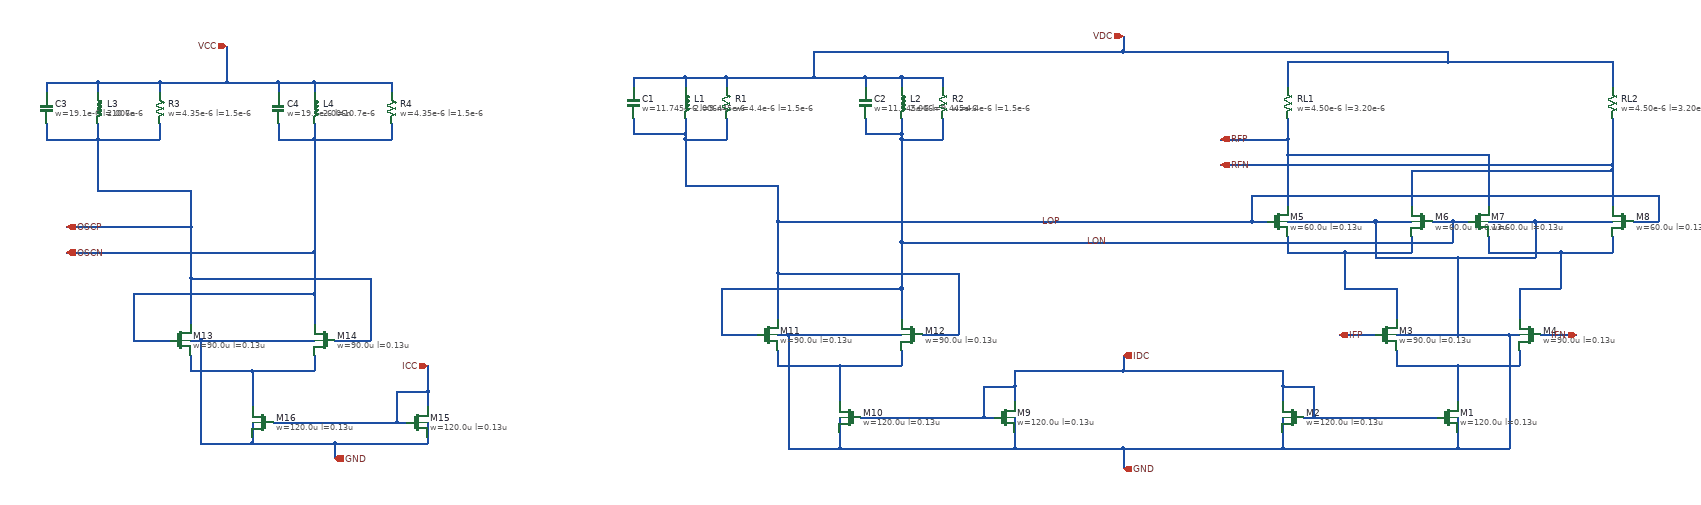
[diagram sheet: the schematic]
v {xschem version=3.4.5 file_version=1.2
}
G {}
K {}
V {}
S {}
E {}
N 530 -10 530 20 {
lab=#net1}
N 650 20 770 20 {
lab=#net1}
N 770 -10 770 20 {
lab=#net1}
N 650 20 650 90 {
lab=#net1}
N 530 20 650 20 {
lab=#net1}
N 370 120 610 120 {
lab=IDC}
N 310 120 310 180 {
lab=GND}
N 650 120 650 180 {
lab=GND}
N 310 60 310 90 {
lab=IDC}
N 310 60 370 60 {
lab=IDC}
N 310 30 310 60 {
lab=IDC}
N 370 60 370 120 {
lab=IDC}
N 350 120 370 120 {
lab=IDC}
N 420 -40 490 -40 {
lab=IFP}
N 810 -40 880 -40 {
lab=IFN}
N 320 -230 320 -200 {
lab=#net2}
N 430 -200 560 -200 {
lab=#net2}
N 560 -230 560 -200 {
lab=#net2}
N 710 -230 710 -200 {
lab=#net3}
N 850 -200 950 -200 {
lab=#net3}
N 950 -230 950 -200 {
lab=#net3}
N 530 -130 530 -70 {
lab=#net2}
N 430 -130 530 -130 {
lab=#net2}
N 430 -200 430 -130 {
lab=#net2}
N 320 -200 430 -200 {
lab=#net2}
N 770 -130 770 -70 {
lab=#net3}
N 770 -130 850 -130 {
lab=#net3}
N 850 -200 850 -130 {
lab=#net3}
N 710 -200 850 -200 {
lab=#net3}
N 640 -260 670 -260 {
lab=LON}
N 990 -260 1040 -260 {
lab=LOP}
N 1040 -310 1040 -260 {
lab=LOP}
N 250 -310 1040 -310 {
lab=LOP}
N 250 -310 250 -260 {
lab=LOP}
N 250 -260 280 -260 {
lab=LOP}
N 640 -260 640 -220 {
lab=LON}
N 600 -260 640 -260 {
lab=LON}
N 320 -390 320 -290 {
lab=RFP}
N 950 -360 950 -290 {
lab=RFN}
N 560 -360 950 -360 {
lab=RFN}
N 950 -370 950 -360 {
lab=RFN}
N 710 -390 710 -290 {
lab=RFP}
N 320 -390 710 -390 {
lab=RFP}
N 320 -420 320 -390 {
lab=RFP}
N 320 -570 320 -520 {
lab=VDC}
N 630 -570 950 -570 {
lab=VDC}
N 950 -570 950 -520 {
lab=VDC}
N 630 -590 630 -570 {
lab=VDC}
N 320 -570 630 -570 {
lab=VDC}
N 0 180 0 220 {
lab=GND}
N 310 180 650 180 {
lab=GND}
N 750 -40 770 -40 {
lab=GND}
N 490 -260 560 -260 {
lab=GND}
N 800 -260 950 -260 {
lab=GND}
N 750 -40 750 180 {
lab=GND}
N 650 -40 750 -40 {
lab=GND}
N 650 180 750 180 {
lab=GND}
N 490 -260 490 -190 {
lab=GND}
N 320 -260 490 -260 {
lab=GND}
N 650 -190 800 -190 {
lab=GND}
N 800 -260 800 -190 {
lab=GND}
N 710 -260 800 -260 {
lab=GND}
N 650 -190 650 -40 {
lab=GND}
N 490 -190 650 -190 {
lab=GND}
N 530 -40 650 -40 {
lab=GND}
N -430 -10 -430 20 {
lab=#net4}
N -670 20 -550 20 {
lab=#net4}
N -670 -10 -670 20 {
lab=#net4}
N -550 20 -550 90 {
lab=#net4}
N -550 20 -430 20 {
lab=#net4}
N -510 120 -270 120 {
lab=IDC}
N -210 120 -210 180 {
lab=GND}
N -550 120 -550 180 {
lab=GND}
N -210 60 -210 90 {
lab=IDC}
N -270 60 -210 60 {
lab=IDC}
N -210 30 -210 60 {
lab=IDC}
N -270 60 -270 120 {
lab=IDC}
N -270 120 -250 120 {
lab=IDC}
N -670 -40 -650 -40 {
lab=GND}
N -550 180 -210 180 {
lab=GND}
N -650 -40 -650 180 {
lab=GND}
N -650 -40 -430 -40 {
lab=GND}
N -650 180 -550 180 {
lab=GND}
N 0 30 310 30 {
lab=IDC}
N -780 -40 -710 -40 {
lab=LON}
N -780 -130 -780 -40 {
lab=LON}
N -780 -130 -430 -130 {
lab=LON}
N -670 -160 -670 -70 {
lab=LOP}
N -430 -130 -430 -70 {
lab=LON}
N -390 -40 -320 -40 {
lab=LOP}
N -320 -160 -320 -40 {
lab=LOP}
N -670 -160 -320 -160 {
lab=LOP}
N -670 -260 -670 -160 {
lab=LOP}
N -430 -220 -430 -130 {
lab=LON}
N -950 -460 -950 -430 {
lab=LOP}
N -950 -540 -950 -520 {
lab=VDC}
N -670 -330 -670 -260 {
lab=LOP}
N -850 -330 -670 -330 {
lab=LOP}
N -850 -420 -850 -330 {
lab=LOP}
N -950 -430 -850 -430 {
lab=LOP}
N -500 -540 -500 -520 {
lab=VDC}
N -500 -460 -500 -430 {
lab=LON}
N -430 -420 -430 -220 {
lab=LON}
N -500 -430 -430 -430 {
lab=LON}
N -600 -540 -500 -540 {
lab=VDC}
N -600 -590 -600 -540 {
lab=VDC}
N 0 -620 0 -590 {
lab=VDC}
N 0 -590 630 -590 {
lab=VDC}
N 190 -420 320 -420 {
lab=RFP}
N 320 -460 320 -420 {
lab=RFP}
N 560 -360 560 -290 {
lab=RFN}
N 190 -370 950 -370 {
lab=RFN}
N 950 -460 950 -370 {
lab=RFN}
N -770 -540 -600 -540 {
lab=VDC}
N -1570 0 -1570 30 {
lab=#net5}
N -1810 30 -1690 30 {
lab=#net5}
N -1810 0 -1810 30 {
lab=#net5}
N -1690 30 -1690 100 {
lab=#net5}
N -1690 30 -1570 30 {
lab=#net5}
N -1650 130 -1410 130 {
lab=ICC}
N -1350 70 -1350 100 {
lab=ICC}
N -1410 70 -1350 70 {
lab=ICC}
N -1410 70 -1410 130 {
lab=ICC}
N -1410 130 -1390 130 {
lab=ICC}
N -1810 -30 -1790 -30 {
lab=VSS}
N -1790 -30 -1570 -30 {
lab=VSS}
N -1920 -30 -1850 -30 {
lab=OSCN}
N -1920 -120 -1920 -30 {
lab=OSCN}
N -1920 -120 -1570 -120 {
lab=OSCN}
N -1810 -150 -1810 -60 {
lab=OSCP}
N -1570 -120 -1570 -60 {
lab=OSCN}
N -1530 -30 -1460 -30 {
lab=OSCP}
N -1460 -150 -1460 -30 {
lab=OSCP}
N -1810 -150 -1460 -150 {
lab=OSCP}
N -2090 -450 -2090 -420 {
lab=OSCP}
N -1870 -450 -1870 -420 {
lab=OSCP}
N -2090 -530 -2090 -510 {
lab=VCC}
N -1870 -530 -1870 -510 {
lab=VCC}
N -1810 -250 -1810 -150 {
lab=OSCP}
N -1990 -320 -1810 -320 {
lab=OSCP}
N -1990 -420 -1990 -320 {
lab=OSCP}
N -2090 -420 -1990 -420 {
lab=OSCP}
N -1640 -530 -1640 -510 {
lab=VCC}
N -1420 -530 -1420 -510 {
lab=VCC}
N -1570 -530 -1420 -530 {
lab=VCC}
N -1640 -450 -1640 -420 {
lab=OSCN}
N -1420 -450 -1420 -420 {
lab=OSCN}
N -1570 -420 -1420 -420 {
lab=OSCN}
N -1570 -200 -1570 -120 {
lab=OSCN}
N -1640 -420 -1570 -420 {
lab=OSCN}
N -1740 -530 -1640 -530 {
lab=VCC}
N -1870 -530 -1740 -530 {
lab=VCC}
N -1990 -530 -1870 -530 {
lab=VCC}
N -1990 -420 -1870 -420 {
lab=OSCP}
N -1570 -420 -1570 -200 {
lab=OSCN}
N -1740 -600 -1740 -530 {
lab=VCC}
N -2050 -250 -1810 -250 {
lab=OSCP}
N -1810 -320 -1810 -250 {
lab=OSCP}
N -2050 -200 -1570 -200 {
lab=OSCN}
N -1350 20 -1350 70 {
lab=ICC}
N -1790 -30 -1790 170 {
lab=VSS}
N -1790 170 -1690 170 {
lab=VSS}
N -1690 130 -1690 170 {
lab=VSS}
N -1530 170 -1350 170 {
lab=VSS}
N -1350 130 -1350 170 {
lab=VSS}
N -1530 170 -1530 200 {
lab=VSS}
N -1690 170 -1530 170 {
lab=VSS}
N -1990 -450 -1990 -420 {
lab=OSCP}
N -1990 -530 -1990 -510 {
lab=VCC}
N -2090 -530 -1990 -530 {
lab=VCC}
N -850 -540 -850 -520 {
lab=VDC}
N -950 -540 -850 -540 {
lab=VDC}
N -850 -460 -850 -430 {
lab=LOP}
N -430 -540 -430 -520 {
lab=VDC}
N -500 -540 -430 -540 {
lab=VDC}
N -430 -460 -430 -430 {
lab=LON}
N -1570 -530 -1570 -510 {
lab=VCC}
N -1640 -530 -1570 -530 {
lab=VCC}
N -1570 -450 -1570 -420 {
lab=OSCN}
N -430 -220 640 -220 {
lab=LON}
N -670 -260 250 -260 {
lab=LOP}
N -770 -540 -770 -520 {
lab=VDC}
N -850 -540 -770 -540 {
lab=VDC}
N -770 -460 -770 -420 {
lab=LOP}
N -850 -420 -770 -420 {
lab=LOP}
N -850 -430 -850 -420 {
lab=LOP}
N -350 -540 -350 -520 {
lab=VDC}
N -430 -540 -350 -540 {
lab=VDC}
N -350 -460 -350 -420 {
lab=LON}
N -430 -420 -350 -420 {
lab=LON}
N -430 -430 -430 -420 {
lab=LON}
N -600 -590 0 -590 {
lab=VDC}
N 0 180 310 180 {
lab=GND}
N 0 0 0 30 {
lab=IDC}
N -210 30 0 30 {
lab=IDC}
N -210 180 0 180 {
lab=GND}
C {sg13g2_pr/sg13_lv_nmos.sym} 580 -260 0 1 {name=M6
l=0.13u
w=60.0u
ng=10
m=1
model=sg13_lv_nmos
spiceprefix=X
}
C {sg13g2_pr/rppd.sym} 950 -490 0 0 {name=RL2
w=4.50e-6
l=3.20e-6
model=rppd
spiceprefix=X
b=0
m=1
}
C {sg13g2_pr/rppd.sym} 320 -490 0 0 {name=RL1
w=4.50e-6
l=3.20e-6
model=rppd
spiceprefix=X
b=0
m=1
}
C {sg13g2_pr/sg13_lv_nmos.sym} 970 -260 0 1 {name=M8
l=0.13u
w=60.0u
ng=10
m=1
model=sg13_lv_nmos
spiceprefix=X
}
C {sg13g2_pr/sg13_lv_nmos.sym} 690 -260 0 0 {name=M7
l=0.13u
w=60.0u
ng=10
m=1
model=sg13_lv_nmos
spiceprefix=X
}
C {sg13g2_pr/sg13_lv_nmos.sym} 300 -260 0 0 {name=M5
l=0.13u
w=60.0u
ng=10
m=1
model=sg13_lv_nmos
spiceprefix=X
}
C {sg13g2_pr/sg13_lv_nmos.sym} 790 -40 0 1 {name=M4
l=0.13u
w=90.0u
ng=15
m=1
model=sg13_lv_nmos
spiceprefix=X
}
C {sg13g2_pr/sg13_lv_nmos.sym} 510 -40 0 0 {name=M3
l=0.13u
w=90.0u
ng=15
m=1
model=sg13_lv_nmos
spiceprefix=X
}
C {sg13g2_pr/sg13_lv_nmos.sym} 330 120 0 1 {name=M2
l=0.13u
w=120.0u
ng=20
m=1
model=sg13_lv_nmos
spiceprefix=X
}
C {sg13g2_pr/sg13_lv_nmos.sym} 630 120 0 0 {name=M1
l=0.13u
w=120.0u
ng=20
m=1
model=sg13_lv_nmos
spiceprefix=X
}
C {iopin.sym} 190 -370 0 1 {name=p4 lab=RFN}
C {iopin.sym} 190 -420 0 1 {name=p5 lab=RFP}
C {iopin.sym} 0 -620 3 0 {name=p6 lab=VDC}
C {iopin.sym} 420 -40 0 1 {name=p1 lab=IFP}
C {iopin.sym} 880 -40 0 0 {name=p7 lab=IFN}
C {iopin.sym} 0 220 3 1 {name=p8 lab=GND}
C {iopin.sym} 0 0 1 1 {name=p9 lab=IDC
}
C {sg13g2_pr/sg13_lv_nmos.sym} -690 -40 0 0 {name=M11
l=0.13u
w=90.0u
ng=15
m=1
model=sg13_lv_nmos
spiceprefix=X
}
C {sg13g2_pr/sg13_lv_nmos.sym} -410 -40 0 1 {name=M12
l=0.13u
w=90.0u
ng=15
m=1
model=sg13_lv_nmos
spiceprefix=X
}
C {sg13g2_pr/sg13_lv_nmos.sym} -230 120 0 0 {name=M9
l=0.13u
w=120.0u
ng=20
m=1
model=sg13_lv_nmos
spiceprefix=X
}
C {sg13g2_pr/sg13_lv_nmos.sym} -530 120 0 1 {name=M10
l=0.13u
w=120.0u
ng=20
m=1
model=sg13_lv_nmos
spiceprefix=X
}
C {sg13g2_pr/cap_cmim.sym} -950 -490 0 0 {name=C1
model=cap_cmim
w=11.745e-6
l=9.445e-6
m=1
spiceprefix=X}
C {sg13g2_pr/rppd.sym} -770 -490 0 0 {name=R1
w=4.4e-6
l=1.5e-6
model=rppd
spiceprefix=X
b=0
m=1
}
C {sg13g2_pr/cap_cmim.sym} -500 -490 0 0 {name=C2
model=cap_cmim
w=11.745e-6
l=9.445e-6
m=1
spiceprefix=X}
C {sg13g2_pr/rppd.sym} -350 -490 0 0 {name=R2
w=4.4e-6
l=1.5e-6
model=rppd
spiceprefix=X
b=0
m=1
}
C {sg13g2_pr/sg13_lv_nmos.sym} -1830 -30 0 0 {name=M13
l=0.13u
w=90.0u
ng=15
m=1
model=sg13_lv_nmos
spiceprefix=X
}
C {sg13g2_pr/sg13_lv_nmos.sym} -1550 -30 0 1 {name=M14
l=0.13u
w=90.0u
ng=15
m=1
model=sg13_lv_nmos
spiceprefix=X
}
C {sg13g2_pr/sg13_lv_nmos.sym} -1370 130 0 0 {name=M15
l=0.13u
w=120.0u
ng=20
m=1
model=sg13_lv_nmos
spiceprefix=X
}
C {sg13g2_pr/sg13_lv_nmos.sym} -1670 130 0 1 {name=M16
l=0.13u
w=120.0u
ng=20
m=1
model=sg13_lv_nmos
spiceprefix=X
}
C {sg13g2_pr/cap_cmim.sym} -2090 -480 0 0 {name=C3
model=cap_cmim
w=19.1e-6
l=10.7e-6
m=1
spiceprefix=X}
C {sg13g2_pr/rppd.sym} -1870 -480 0 0 {name=R3
w=4.35e-6
l=1.5e-6
model=rppd
spiceprefix=X
b=0
m=1
}
C {sg13g2_pr/cap_cmim.sym} -1640 -480 0 0 {name=C4
model=cap_cmim
w=19.1e-6
l=10.7e-6
m=1
spiceprefix=X}
C {sg13g2_pr/rppd.sym} -1420 -480 0 0 {name=R4
w=4.35e-6
l=1.5e-6
model=rppd
spiceprefix=X
b=0
m=1
}
C {iopin.sym} -2050 -200 0 1 {name=p2 lab=OSCN}
C {iopin.sym} -2050 -250 0 1 {name=p3 lab=OSCP}
C {iopin.sym} -1740 -600 3 0 {name=p10 lab=VCC}
C {iopin.sym} -1350 20 3 0 {name=p11 lab=ICC}
C {iopin.sym} -1530 200 3 1 {name=p12 lab=GND
}
C {ind.sym} -1990 -480 0 0 {name=L3
m=1
value=2.006n
footprint=1206
device=inductor}
C {ind.sym} -850 -490 0 0 {name=L1
m=1
value=2.006n
footprint=1206
device=inductor}
C {ind.sym} -430 -490 0 0 {name=L2
m=1
value=2.006n
footprint=1206
device=inductor}
C {ind.sym} -1570 -480 0 0 {name=L4
m=1
value=2.006n
footprint=1206
device=inductor}
C {lab_wire.sym} -120 -260 0 0 {name=p15 sig_type=std_logic lab=LOP
}
C {lab_wire.sym} -30 -220 0 0 {name=p13 sig_type=std_logic lab=LON
}
